VERSION 5.6 ;

BUSBITCHARS "[]" ;
DIVIDERCHAR "/" ;

UNITS
  DATABASE MICRONS 2000 ;
END UNITS

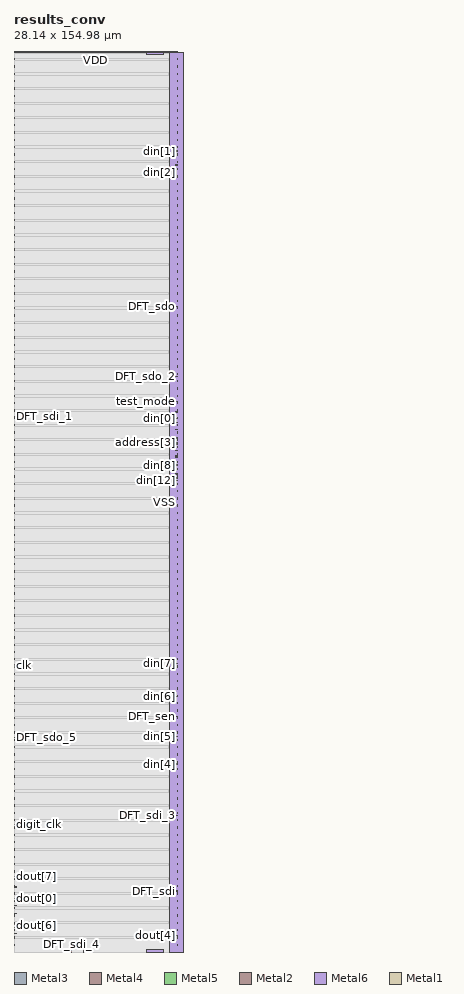
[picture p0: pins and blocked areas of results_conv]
MACRO results_conv
  CLASS BLOCK ;
  FOREIGN results_conv 0 0 ;
  ORIGIN 0.0000 0.0000 ;
  SIZE 28.1400 BY 154.9800 ;
  SYMMETRY X Y R90 ;
  PIN clk
    DIRECTION INPUT ;
    USE SIGNAL ;
    ANTENNAGATEAREA  0.039 ;
    PORT
      LAYER Metal3 ;
        RECT 0.0000 49.3850 0.4000 49.4550 ;
    END
  END clk
  PIN reset
    DIRECTION INPUT ;
    USE SIGNAL ;
    ANTENNAGATEAREA  0.039 ;
    PORT
      LAYER Metal4 ;
        RECT 11.9350 0.0000 12.0050 0.4000 ;
    END
  END reset
  PIN rcc_clk
    DIRECTION INPUT ;
    USE SIGNAL ;
    ANTENNAGATEAREA  0.039 ;
    PORT
      LAYER Metal3 ;
        RECT 27.7400 92.9250 28.1400 92.9950 ;
    END
  END rcc_clk
  PIN address[3]
    DIRECTION INPUT ;
    USE SIGNAL ;
    ANTENNAGATEAREA  0.039 ;
    PORT
      LAYER Metal5 ;
        RECT 27.7400 87.7450 28.1400 87.8150 ;
    END
  END address[3]
  PIN address[2]
    DIRECTION INPUT ;
    USE SIGNAL ;
    ANTENNAGATEAREA  0.039 ;
    PORT
      LAYER Metal3 ;
        RECT 27.7400 88.4450 28.1400 88.5150 ;
    END
  END address[2]
  PIN address[1]
    DIRECTION INPUT ;
    USE SIGNAL ;
    ANTENNAGATEAREA  0.039 ;
    PORT
      LAYER Metal5 ;
        RECT 27.7400 88.5850 28.1400 88.6550 ;
    END
  END address[1]
  PIN address[0]
    DIRECTION INPUT ;
    USE SIGNAL ;
    ANTENNAGATEAREA  0.039 ;
    PORT
      LAYER Metal5 ;
        RECT 27.7400 89.9850 28.1400 90.0550 ;
    END
  END address[0]
  PIN din[15]
    DIRECTION INPUT ;
    USE SIGNAL ;
    ANTENNAGATEAREA  0.039 ;
    PORT
      LAYER Metal5 ;
        RECT 27.7400 85.2250 28.1400 85.2950 ;
    END
  END din[15]
  PIN din[14]
    DIRECTION INPUT ;
    USE SIGNAL ;
    ANTENNAGATEAREA  0.039 ;
    PORT
      LAYER Metal5 ;
        RECT 27.7400 82.2850 28.1400 82.3550 ;
    END
  END din[14]
  PIN din[13]
    DIRECTION INPUT ;
    USE SIGNAL ;
    ANTENNAGATEAREA  0.039 ;
    PORT
      LAYER Metal3 ;
        RECT 27.7400 81.5850 28.1400 81.6550 ;
    END
  END din[13]
  PIN din[12]
    DIRECTION INPUT ;
    USE SIGNAL ;
    ANTENNAGATEAREA  0.039 ;
    PORT
      LAYER Metal5 ;
        RECT 27.7400 81.1650 28.1400 81.2350 ;
    END
  END din[12]
  PIN din[11]
    DIRECTION INPUT ;
    USE SIGNAL ;
    ANTENNAGATEAREA  0.039 ;
    PORT
      LAYER Metal5 ;
        RECT 27.7400 91.1050 28.1400 91.1750 ;
    END
  END din[11]
  PIN din[10]
    DIRECTION INPUT ;
    USE SIGNAL ;
    ANTENNAGATEAREA  0.039 ;
    PORT
      LAYER Metal3 ;
        RECT 27.7400 86.3450 28.1400 86.4150 ;
    END
  END din[10]
  PIN din[9]
    DIRECTION INPUT ;
    USE SIGNAL ;
    ANTENNAGATEAREA  0.039 ;
    PORT
      LAYER Metal3 ;
        RECT 27.7400 85.3650 28.1400 85.4350 ;
    END
  END din[9]
  PIN din[8]
    DIRECTION INPUT ;
    USE SIGNAL ;
    ANTENNAGATEAREA  0.039 ;
    PORT
      LAYER Metal3 ;
        RECT 27.7400 83.8250 28.1400 83.8950 ;
    END
  END din[8]
  PIN din[7]
    DIRECTION INPUT ;
    USE SIGNAL ;
    ANTENNAGATEAREA  0.039 ;
    PORT
      LAYER Metal5 ;
        RECT 27.7400 49.6650 28.1400 49.7350 ;
    END
  END din[7]
  PIN din[6]
    DIRECTION INPUT ;
    USE SIGNAL ;
    ANTENNAGATEAREA  0.039 ;
    PORT
      LAYER Metal5 ;
        RECT 27.7400 43.9250 28.1400 43.9950 ;
    END
  END din[6]
  PIN din[5]
    DIRECTION INPUT ;
    USE SIGNAL ;
    ANTENNAGATEAREA  0.039 ;
    PORT
      LAYER Metal5 ;
        RECT 27.7400 37.0650 28.1400 37.1350 ;
    END
  END din[5]
  PIN din[4]
    DIRECTION INPUT ;
    USE SIGNAL ;
    ANTENNAGATEAREA  0.039 ;
    PORT
      LAYER Metal5 ;
        RECT 27.7400 32.3050 28.1400 32.3750 ;
    END
  END din[4]
  PIN din[3]
    DIRECTION INPUT ;
    USE SIGNAL ;
    ANTENNAGATEAREA  0.039 ;
    PORT
      LAYER Metal5 ;
        RECT 27.7400 87.4650 28.1400 87.5350 ;
    END
  END din[3]
  PIN din[2]
    DIRECTION INPUT ;
    USE SIGNAL ;
    ANTENNAGATEAREA  0.039 ;
    PORT
      LAYER Metal5 ;
        RECT 27.7400 135.4850 28.1400 135.5550 ;
    END
  END din[2]
  PIN din[1]
    DIRECTION INPUT ;
    USE SIGNAL ;
    ANTENNAGATEAREA  0.039 ;
    PORT
      LAYER Metal3 ;
        RECT 27.7400 137.8650 28.1400 137.9350 ;
    END
  END din[1]
  PIN din[0]
    DIRECTION INPUT ;
    USE SIGNAL ;
    ANTENNAGATEAREA  0.039 ;
    PORT
      LAYER Metal3 ;
        RECT 27.7400 91.8050 28.1400 91.8750 ;
    END
  END din[0]
  PIN digit_clk
    DIRECTION OUTPUT ;
    USE SIGNAL ;
    ANTENNADIFFAREA 1.7285  LAYER Metal1 ;
    PORT
      LAYER Metal5 ;
        RECT 0.0000 21.9450 0.4000 22.0150 ;
    END
  END digit_clk
  PIN dout[7]
    DIRECTION OUTPUT ;
    USE SIGNAL ;
    ANTENNADIFFAREA 1.7285  LAYER Metal1 ;
    PORT
      LAYER Metal5 ;
        RECT 0.0000 12.9850 0.4000 13.0550 ;
    END
  END dout[7]
  PIN dout[6]
    DIRECTION OUTPUT ;
    USE SIGNAL ;
    ANTENNADIFFAREA 1.7285  LAYER Metal1 ;
    PORT
      LAYER Metal5 ;
        RECT 0.0000 3.1850 0.4000 3.2550 ;
    END
  END dout[6]
  PIN dout[5]
    DIRECTION OUTPUT ;
    USE SIGNAL ;
    ANTENNADIFFAREA 1.7285  LAYER Metal1 ;
    PORT
      LAYER Metal3 ;
        RECT 0.0000 4.1650 0.4000 4.2350 ;
    END
  END dout[5]
  PIN dout[4]
    DIRECTION OUTPUT ;
    USE SIGNAL ;
    ANTENNADIFFAREA 1.7285  LAYER Metal1 ;
    PORT
      LAYER Metal3 ;
        RECT 27.7400 2.7650 28.1400 2.8350 ;
    END
  END dout[4]
  PIN dout[3]
    DIRECTION OUTPUT ;
    USE SIGNAL ;
    ANTENNADIFFAREA 1.7285  LAYER Metal1 ;
    PORT
      LAYER Metal5 ;
        RECT 0.0000 4.7250 0.4000 4.7950 ;
    END
  END dout[3]
  PIN dout[2]
    DIRECTION OUTPUT ;
    USE SIGNAL ;
    ANTENNADIFFAREA 1.7285  LAYER Metal1 ;
    PORT
      LAYER Metal3 ;
        RECT 0.0000 6.5450 0.4000 6.6150 ;
    END
  END dout[2]
  PIN dout[1]
    DIRECTION OUTPUT ;
    USE SIGNAL ;
    ANTENNADIFFAREA 1.7285  LAYER Metal1 ;
    PORT
      LAYER Metal5 ;
        RECT 0.0000 7.9450 0.4000 8.0150 ;
    END
  END dout[1]
  PIN dout[0]
    DIRECTION OUTPUT ;
    USE SIGNAL ;
    ANTENNADIFFAREA 1.7285  LAYER Metal1 ;
    PORT
      LAYER Metal3 ;
        RECT 0.0000 9.2050 0.4000 9.2750 ;
    END
  END dout[0]
  PIN dout_flag
    DIRECTION OUTPUT ;
    USE SIGNAL ;
    ANTENNADIFFAREA 1.7285  LAYER Metal1 ;
    PORT
      LAYER Metal3 ;
        RECT 0.0000 11.1650 0.4000 11.2350 ;
    END
  END dout_flag
  PIN test_mode
    DIRECTION INPUT ;
    USE SIGNAL ;
    ANTENNAGATEAREA  0.039 ;
    PORT
      LAYER Metal5 ;
        RECT 27.7400 94.7450 28.1400 94.8150 ;
    END
  END test_mode
  PIN DFT_sdi
    DIRECTION INPUT ;
    USE SIGNAL ;
    ANTENNAGATEAREA  0.039 ;
    PORT
      LAYER Metal5 ;
        RECT 27.7400 10.4650 28.1400 10.5350 ;
    END
  END DFT_sdi
  PIN DFT_sen
    DIRECTION INPUT ;
    USE SIGNAL ;
    ANTENNAGATEAREA  0.039 ;
    PORT
      LAYER Metal3 ;
        RECT 27.7400 40.5650 28.1400 40.6350 ;
    END
  END DFT_sen
  PIN DFT_sdo
    DIRECTION OUTPUT ;
    USE SIGNAL ;
    ANTENNADIFFAREA 1.7285  LAYER Metal1 ;
    PORT
      LAYER Metal3 ;
        RECT 27.7400 111.1250 28.1400 111.1950 ;
    END
  END DFT_sdo
  PIN DFT_sdi_1
    DIRECTION INPUT ;
    USE SIGNAL ;
    ANTENNAGATEAREA  0.039 ;
    PORT
      LAYER Metal5 ;
        RECT 0.0000 92.2250 0.4000 92.2950 ;
    END
  END DFT_sdi_1
  PIN DFT_sdo_2
    DIRECTION OUTPUT ;
    USE SIGNAL ;
    ANTENNADIFFAREA 1.7285  LAYER Metal1 ;
    PORT
      LAYER Metal5 ;
        RECT 27.7400 99.0850 28.1400 99.1550 ;
    END
  END DFT_sdo_2
  PIN DFT_sdi_3
    DIRECTION INPUT ;
    USE SIGNAL ;
    ANTENNAGATEAREA  0.039 ;
    PORT
      LAYER Metal5 ;
        RECT 27.7400 23.4850 28.1400 23.5550 ;
    END
  END DFT_sdi_3
  PIN DFT_sdi_4
    DIRECTION INPUT ;
    USE SIGNAL ;
    ANTENNAGATEAREA  0.039 ;
    PORT
      LAYER Metal2 ;
        RECT 9.8350 0.0000 9.9050 0.4000 ;
    END
  END DFT_sdi_4
  PIN DFT_sdo_5
    DIRECTION OUTPUT ;
    USE SIGNAL ;
    ANTENNADIFFAREA 1.7285  LAYER Metal1 ;
    PORT
      LAYER Metal3 ;
        RECT 0.0000 36.9250 0.4000 36.9950 ;
    END
  END DFT_sdo_5
  PIN VSS
    DIRECTION INOUT ;
    USE GROUND ;
    PORT
      LAYER Metal6 ;
        RECT 26.7600 0.0000 29.7600 154.9800 ;
    END
    PORT
      LAYER Metal1 ;
        RECT 28.0700 15.0050 28.1400 15.2350 ;
    END
    PORT
      LAYER Metal1 ;
        RECT 0.0000 15.0050 0.0700 15.2350 ;
    END
    PORT
      LAYER Metal1 ;
        RECT 28.0700 12.4850 28.1400 12.7150 ;
    END
    PORT
      LAYER Metal1 ;
        RECT 0.0000 12.4850 0.0700 12.7150 ;
    END
    PORT
      LAYER Metal1 ;
        RECT 28.0700 9.9650 28.1400 10.1950 ;
    END
    PORT
      LAYER Metal1 ;
        RECT 0.0000 9.9650 0.0700 10.1950 ;
    END
    PORT
      LAYER Metal1 ;
        RECT 28.0700 7.4450 28.1400 7.6750 ;
    END
    PORT
      LAYER Metal1 ;
        RECT 0.0000 7.4450 0.0700 7.6750 ;
    END
    PORT
      LAYER Metal1 ;
        RECT 28.0700 2.4050 28.1400 2.6350 ;
    END
    PORT
      LAYER Metal1 ;
        RECT 0.0000 2.4050 0.0700 2.6350 ;
    END
    PORT
      LAYER Metal1 ;
        RECT 28.0700 4.9250 28.1400 5.1550 ;
    END
    PORT
      LAYER Metal1 ;
        RECT 0.0000 4.9250 0.0700 5.1550 ;
    END
    PORT
      LAYER Metal1 ;
        RECT 28.0700 37.6850 28.1400 37.9150 ;
    END
    PORT
      LAYER Metal1 ;
        RECT 0.0000 37.6850 0.0700 37.9150 ;
    END
    PORT
      LAYER Metal1 ;
        RECT 28.0700 35.1650 28.1400 35.3950 ;
    END
    PORT
      LAYER Metal1 ;
        RECT 0.0000 35.1650 0.0700 35.3950 ;
    END
    PORT
      LAYER Metal1 ;
        RECT 28.0700 32.6450 28.1400 32.8750 ;
    END
    PORT
      LAYER Metal1 ;
        RECT 0.0000 32.6450 0.0700 32.8750 ;
    END
    PORT
      LAYER Metal1 ;
        RECT 28.0700 30.1250 28.1400 30.3550 ;
    END
    PORT
      LAYER Metal1 ;
        RECT 0.0000 30.1250 0.0700 30.3550 ;
    END
    PORT
      LAYER Metal1 ;
        RECT 28.0700 27.6050 28.1400 27.8350 ;
    END
    PORT
      LAYER Metal1 ;
        RECT 0.0000 27.6050 0.0700 27.8350 ;
    END
    PORT
      LAYER Metal1 ;
        RECT 28.0700 25.0850 28.1400 25.3150 ;
    END
    PORT
      LAYER Metal1 ;
        RECT 0.0000 25.0850 0.0700 25.3150 ;
    END
    PORT
      LAYER Metal1 ;
        RECT 28.0700 22.5650 28.1400 22.7950 ;
    END
    PORT
      LAYER Metal1 ;
        RECT 0.0000 22.5650 0.0700 22.7950 ;
    END
    PORT
      LAYER Metal1 ;
        RECT 28.0700 20.0450 28.1400 20.2750 ;
    END
    PORT
      LAYER Metal1 ;
        RECT 0.0000 20.0450 0.0700 20.2750 ;
    END
    PORT
      LAYER Metal1 ;
        RECT 28.0700 17.5250 28.1400 17.7550 ;
    END
    PORT
      LAYER Metal1 ;
        RECT 0.0000 17.5250 0.0700 17.7550 ;
    END
    PORT
      LAYER Metal1 ;
        RECT 28.0700 57.8450 28.1400 58.0750 ;
    END
    PORT
      LAYER Metal1 ;
        RECT 0.0000 57.8450 0.0700 58.0750 ;
    END
    PORT
      LAYER Metal1 ;
        RECT 28.0700 60.3650 28.1400 60.5950 ;
    END
    PORT
      LAYER Metal1 ;
        RECT 0.0000 60.3650 0.0700 60.5950 ;
    END
    PORT
      LAYER Metal1 ;
        RECT 28.0700 55.3250 28.1400 55.5550 ;
    END
    PORT
      LAYER Metal1 ;
        RECT 0.0000 55.3250 0.0700 55.5550 ;
    END
    PORT
      LAYER Metal1 ;
        RECT 28.0700 52.8050 28.1400 53.0350 ;
    END
    PORT
      LAYER Metal1 ;
        RECT 0.0000 52.8050 0.0700 53.0350 ;
    END
    PORT
      LAYER Metal1 ;
        RECT 28.0700 50.2850 28.1400 50.5150 ;
    END
    PORT
      LAYER Metal1 ;
        RECT 0.0000 50.2850 0.0700 50.5150 ;
    END
    PORT
      LAYER Metal1 ;
        RECT 28.0700 47.7650 28.1400 47.9950 ;
    END
    PORT
      LAYER Metal1 ;
        RECT 0.0000 47.7650 0.0700 47.9950 ;
    END
    PORT
      LAYER Metal1 ;
        RECT 28.0700 45.2450 28.1400 45.4750 ;
    END
    PORT
      LAYER Metal1 ;
        RECT 0.0000 45.2450 0.0700 45.4750 ;
    END
    PORT
      LAYER Metal1 ;
        RECT 28.0700 42.7250 28.1400 42.9550 ;
    END
    PORT
      LAYER Metal1 ;
        RECT 0.0000 42.7250 0.0700 42.9550 ;
    END
    PORT
      LAYER Metal1 ;
        RECT 28.0700 40.2050 28.1400 40.4350 ;
    END
    PORT
      LAYER Metal1 ;
        RECT 0.0000 40.2050 0.0700 40.4350 ;
    END
    PORT
      LAYER Metal1 ;
        RECT 28.0700 78.0050 28.1400 78.2350 ;
    END
    PORT
      LAYER Metal1 ;
        RECT 0.0000 78.0050 0.0700 78.2350 ;
    END
    PORT
      LAYER Metal1 ;
        RECT 28.0700 75.4850 28.1400 75.7150 ;
    END
    PORT
      LAYER Metal1 ;
        RECT 0.0000 75.4850 0.0700 75.7150 ;
    END
    PORT
      LAYER Metal1 ;
        RECT 28.0700 72.9650 28.1400 73.1950 ;
    END
    PORT
      LAYER Metal1 ;
        RECT 0.0000 72.9650 0.0700 73.1950 ;
    END
    PORT
      LAYER Metal1 ;
        RECT 28.0700 80.5250 28.1400 80.7550 ;
    END
    PORT
      LAYER Metal1 ;
        RECT 0.0000 80.5250 0.0700 80.7550 ;
    END
    PORT
      LAYER Metal1 ;
        RECT 28.0700 83.0450 28.1400 83.2750 ;
    END
    PORT
      LAYER Metal1 ;
        RECT 0.0000 83.0450 0.0700 83.2750 ;
    END
    PORT
      LAYER Metal1 ;
        RECT 28.0700 70.4450 28.1400 70.6750 ;
    END
    PORT
      LAYER Metal1 ;
        RECT 0.0000 70.4450 0.0700 70.6750 ;
    END
    PORT
      LAYER Metal1 ;
        RECT 28.0700 67.9250 28.1400 68.1550 ;
    END
    PORT
      LAYER Metal1 ;
        RECT 0.0000 67.9250 0.0700 68.1550 ;
    END
    PORT
      LAYER Metal1 ;
        RECT 28.0700 65.4050 28.1400 65.6350 ;
    END
    PORT
      LAYER Metal1 ;
        RECT 0.0000 65.4050 0.0700 65.6350 ;
    END
    PORT
      LAYER Metal1 ;
        RECT 28.0700 62.8850 28.1400 63.1150 ;
    END
    PORT
      LAYER Metal1 ;
        RECT 0.0000 62.8850 0.0700 63.1150 ;
    END
    PORT
      LAYER Metal1 ;
        RECT 28.0700 105.7250 28.1400 105.9550 ;
    END
    PORT
      LAYER Metal1 ;
        RECT 0.0000 105.7250 0.0700 105.9550 ;
    END
    PORT
      LAYER Metal1 ;
        RECT 28.0700 103.2050 28.1400 103.4350 ;
    END
    PORT
      LAYER Metal1 ;
        RECT 0.0000 103.2050 0.0700 103.4350 ;
    END
    PORT
      LAYER Metal1 ;
        RECT 28.0700 100.6850 28.1400 100.9150 ;
    END
    PORT
      LAYER Metal1 ;
        RECT 0.0000 100.6850 0.0700 100.9150 ;
    END
    PORT
      LAYER Metal1 ;
        RECT 28.0700 98.1650 28.1400 98.3950 ;
    END
    PORT
      LAYER Metal1 ;
        RECT 0.0000 98.1650 0.0700 98.3950 ;
    END
    PORT
      LAYER Metal1 ;
        RECT 28.0700 95.6450 28.1400 95.8750 ;
    END
    PORT
      LAYER Metal1 ;
        RECT 0.0000 95.6450 0.0700 95.8750 ;
    END
    PORT
      LAYER Metal1 ;
        RECT 28.0700 93.1250 28.1400 93.3550 ;
    END
    PORT
      LAYER Metal1 ;
        RECT 0.0000 93.1250 0.0700 93.3550 ;
    END
    PORT
      LAYER Metal1 ;
        RECT 28.0700 90.6050 28.1400 90.8350 ;
    END
    PORT
      LAYER Metal1 ;
        RECT 0.0000 90.6050 0.0700 90.8350 ;
    END
    PORT
      LAYER Metal1 ;
        RECT 28.0700 88.0850 28.1400 88.3150 ;
    END
    PORT
      LAYER Metal1 ;
        RECT 0.0000 88.0850 0.0700 88.3150 ;
    END
    PORT
      LAYER Metal1 ;
        RECT 28.0700 85.5650 28.1400 85.7950 ;
    END
    PORT
      LAYER Metal1 ;
        RECT 0.0000 85.5650 0.0700 85.7950 ;
    END
    PORT
      LAYER Metal1 ;
        RECT 28.0700 128.4050 28.1400 128.6350 ;
    END
    PORT
      LAYER Metal1 ;
        RECT 0.0000 128.4050 0.0700 128.6350 ;
    END
    PORT
      LAYER Metal1 ;
        RECT 28.0700 125.8850 28.1400 126.1150 ;
    END
    PORT
      LAYER Metal1 ;
        RECT 0.0000 125.8850 0.0700 126.1150 ;
    END
    PORT
      LAYER Metal1 ;
        RECT 28.0700 123.3650 28.1400 123.5950 ;
    END
    PORT
      LAYER Metal1 ;
        RECT 0.0000 123.3650 0.0700 123.5950 ;
    END
    PORT
      LAYER Metal1 ;
        RECT 28.0700 120.8450 28.1400 121.0750 ;
    END
    PORT
      LAYER Metal1 ;
        RECT 0.0000 120.8450 0.0700 121.0750 ;
    END
    PORT
      LAYER Metal1 ;
        RECT 28.0700 118.3250 28.1400 118.5550 ;
    END
    PORT
      LAYER Metal1 ;
        RECT 0.0000 118.3250 0.0700 118.5550 ;
    END
    PORT
      LAYER Metal1 ;
        RECT 28.0700 115.8050 28.1400 116.0350 ;
    END
    PORT
      LAYER Metal1 ;
        RECT 0.0000 115.8050 0.0700 116.0350 ;
    END
    PORT
      LAYER Metal1 ;
        RECT 28.0700 113.2850 28.1400 113.5150 ;
    END
    PORT
      LAYER Metal1 ;
        RECT 0.0000 113.2850 0.0700 113.5150 ;
    END
    PORT
      LAYER Metal1 ;
        RECT 28.0700 110.7650 28.1400 110.9950 ;
    END
    PORT
      LAYER Metal1 ;
        RECT 0.0000 110.7650 0.0700 110.9950 ;
    END
    PORT
      LAYER Metal1 ;
        RECT 28.0700 108.2450 28.1400 108.4750 ;
    END
    PORT
      LAYER Metal1 ;
        RECT 0.0000 108.2450 0.0700 108.4750 ;
    END
    PORT
      LAYER Metal1 ;
        RECT 28.0700 151.0850 28.1400 151.3150 ;
    END
    PORT
      LAYER Metal1 ;
        RECT 0.0000 151.0850 0.0700 151.3150 ;
    END
    PORT
      LAYER Metal1 ;
        RECT 28.0700 141.0050 28.1400 141.2350 ;
    END
    PORT
      LAYER Metal1 ;
        RECT 0.0000 141.0050 0.0700 141.2350 ;
    END
    PORT
      LAYER Metal1 ;
        RECT 28.0700 143.5250 28.1400 143.7550 ;
    END
    PORT
      LAYER Metal1 ;
        RECT 0.0000 143.5250 0.0700 143.7550 ;
    END
    PORT
      LAYER Metal1 ;
        RECT 28.0700 146.0450 28.1400 146.2750 ;
    END
    PORT
      LAYER Metal1 ;
        RECT 0.0000 146.0450 0.0700 146.2750 ;
    END
    PORT
      LAYER Metal1 ;
        RECT 28.0700 148.5650 28.1400 148.7950 ;
    END
    PORT
      LAYER Metal1 ;
        RECT 0.0000 148.5650 0.0700 148.7950 ;
    END
    PORT
      LAYER Metal1 ;
        RECT 28.0700 138.4850 28.1400 138.7150 ;
    END
    PORT
      LAYER Metal1 ;
        RECT 0.0000 138.4850 0.0700 138.7150 ;
    END
    PORT
      LAYER Metal1 ;
        RECT 28.0700 133.4450 28.1400 133.6750 ;
    END
    PORT
      LAYER Metal1 ;
        RECT 0.0000 133.4450 0.0700 133.6750 ;
    END
    PORT
      LAYER Metal1 ;
        RECT 28.0700 135.9650 28.1400 136.1950 ;
    END
    PORT
      LAYER Metal1 ;
        RECT 0.0000 135.9650 0.0700 136.1950 ;
    END
    PORT
      LAYER Metal1 ;
        RECT 28.0700 130.9250 28.1400 131.1550 ;
    END
    PORT
      LAYER Metal1 ;
        RECT 0.0000 130.9250 0.0700 131.1550 ;
    END
    PORT
      LAYER Metal1 ;
        RECT 28.0700 153.6050 28.1400 153.8350 ;
    END
    PORT
      LAYER Metal1 ;
        RECT 0.0000 153.6050 0.0700 153.8350 ;
    END
  END VSS
  PIN VDD
    DIRECTION INOUT ;
    USE POWER ;
    PORT
      LAYER Metal1 ;
        RECT 0.0000 154.8650 28.1400 155.0950 ;
    END
    PORT
      LAYER Metal6 ;
        RECT 22.7600 0.0000 25.7600 0.4000 ;
    END
    PORT
      LAYER Metal6 ;
        RECT 22.7600 154.5800 25.7600 154.9800 ;
    END
    PORT
      LAYER Metal1 ;
        RECT 28.0700 13.7450 28.1400 13.9750 ;
    END
    PORT
      LAYER Metal1 ;
        RECT 0.0000 13.7450 0.0700 13.9750 ;
    END
    PORT
      LAYER Metal1 ;
        RECT 28.0700 11.2250 28.1400 11.4550 ;
    END
    PORT
      LAYER Metal1 ;
        RECT 0.0000 11.2250 0.0700 11.4550 ;
    END
    PORT
      LAYER Metal1 ;
        RECT 28.0700 8.7050 28.1400 8.9350 ;
    END
    PORT
      LAYER Metal1 ;
        RECT 0.0000 8.7050 0.0700 8.9350 ;
    END
    PORT
      LAYER Metal1 ;
        RECT 28.0700 6.1850 28.1400 6.4150 ;
    END
    PORT
      LAYER Metal1 ;
        RECT 0.0000 6.1850 0.0700 6.4150 ;
    END
    PORT
      LAYER Metal1 ;
        RECT 28.0700 3.6650 28.1400 3.8950 ;
    END
    PORT
      LAYER Metal1 ;
        RECT 0.0000 3.6650 0.0700 3.8950 ;
    END
    PORT
      LAYER Metal1 ;
        RECT 28.0700 1.1450 28.1400 1.3750 ;
    END
    PORT
      LAYER Metal1 ;
        RECT 0.0000 1.1450 0.0700 1.3750 ;
    END
    PORT
      LAYER Metal1 ;
        RECT 28.0700 16.2650 28.1400 16.4950 ;
    END
    PORT
      LAYER Metal1 ;
        RECT 0.0000 16.2650 0.0700 16.4950 ;
    END
    PORT
      LAYER Metal1 ;
        RECT 28.0700 36.4250 28.1400 36.6550 ;
    END
    PORT
      LAYER Metal1 ;
        RECT 0.0000 36.4250 0.0700 36.6550 ;
    END
    PORT
      LAYER Metal1 ;
        RECT 28.0700 33.9050 28.1400 34.1350 ;
    END
    PORT
      LAYER Metal1 ;
        RECT 0.0000 33.9050 0.0700 34.1350 ;
    END
    PORT
      LAYER Metal1 ;
        RECT 28.0700 31.3850 28.1400 31.6150 ;
    END
    PORT
      LAYER Metal1 ;
        RECT 0.0000 31.3850 0.0700 31.6150 ;
    END
    PORT
      LAYER Metal1 ;
        RECT 28.0700 28.8650 28.1400 29.0950 ;
    END
    PORT
      LAYER Metal1 ;
        RECT 0.0000 28.8650 0.0700 29.0950 ;
    END
    PORT
      LAYER Metal1 ;
        RECT 28.0700 23.8250 28.1400 24.0550 ;
    END
    PORT
      LAYER Metal1 ;
        RECT 0.0000 23.8250 0.0700 24.0550 ;
    END
    PORT
      LAYER Metal1 ;
        RECT 28.0700 26.3450 28.1400 26.5750 ;
    END
    PORT
      LAYER Metal1 ;
        RECT 0.0000 26.3450 0.0700 26.5750 ;
    END
    PORT
      LAYER Metal1 ;
        RECT 28.0700 21.3050 28.1400 21.5350 ;
    END
    PORT
      LAYER Metal1 ;
        RECT 0.0000 21.3050 0.0700 21.5350 ;
    END
    PORT
      LAYER Metal1 ;
        RECT 28.0700 18.7850 28.1400 19.0150 ;
    END
    PORT
      LAYER Metal1 ;
        RECT 0.0000 18.7850 0.0700 19.0150 ;
    END
    PORT
      LAYER Metal1 ;
        RECT 28.0700 56.5850 28.1400 56.8150 ;
    END
    PORT
      LAYER Metal1 ;
        RECT 0.0000 56.5850 0.0700 56.8150 ;
    END
    PORT
      LAYER Metal1 ;
        RECT 28.0700 59.1050 28.1400 59.3350 ;
    END
    PORT
      LAYER Metal1 ;
        RECT 0.0000 59.1050 0.0700 59.3350 ;
    END
    PORT
      LAYER Metal1 ;
        RECT 28.0700 54.0650 28.1400 54.2950 ;
    END
    PORT
      LAYER Metal1 ;
        RECT 0.0000 54.0650 0.0700 54.2950 ;
    END
    PORT
      LAYER Metal1 ;
        RECT 28.0700 51.5450 28.1400 51.7750 ;
    END
    PORT
      LAYER Metal1 ;
        RECT 0.0000 51.5450 0.0700 51.7750 ;
    END
    PORT
      LAYER Metal1 ;
        RECT 28.0700 49.0250 28.1400 49.2550 ;
    END
    PORT
      LAYER Metal1 ;
        RECT 0.0000 49.0250 0.0700 49.2550 ;
    END
    PORT
      LAYER Metal1 ;
        RECT 28.0700 46.5050 28.1400 46.7350 ;
    END
    PORT
      LAYER Metal1 ;
        RECT 0.0000 46.5050 0.0700 46.7350 ;
    END
    PORT
      LAYER Metal1 ;
        RECT 28.0700 43.9850 28.1400 44.2150 ;
    END
    PORT
      LAYER Metal1 ;
        RECT 0.0000 43.9850 0.0700 44.2150 ;
    END
    PORT
      LAYER Metal1 ;
        RECT 28.0700 41.4650 28.1400 41.6950 ;
    END
    PORT
      LAYER Metal1 ;
        RECT 0.0000 41.4650 0.0700 41.6950 ;
    END
    PORT
      LAYER Metal1 ;
        RECT 28.0700 38.9450 28.1400 39.1750 ;
    END
    PORT
      LAYER Metal1 ;
        RECT 0.0000 38.9450 0.0700 39.1750 ;
    END
    PORT
      LAYER Metal1 ;
        RECT 28.0700 76.7450 28.1400 76.9750 ;
    END
    PORT
      LAYER Metal1 ;
        RECT 0.0000 76.7450 0.0700 76.9750 ;
    END
    PORT
      LAYER Metal1 ;
        RECT 28.0700 71.7050 28.1400 71.9350 ;
    END
    PORT
      LAYER Metal1 ;
        RECT 0.0000 71.7050 0.0700 71.9350 ;
    END
    PORT
      LAYER Metal1 ;
        RECT 28.0700 74.2250 28.1400 74.4550 ;
    END
    PORT
      LAYER Metal1 ;
        RECT 0.0000 74.2250 0.0700 74.4550 ;
    END
    PORT
      LAYER Metal1 ;
        RECT 28.0700 79.2650 28.1400 79.4950 ;
    END
    PORT
      LAYER Metal1 ;
        RECT 0.0000 79.2650 0.0700 79.4950 ;
    END
    PORT
      LAYER Metal1 ;
        RECT 28.0700 81.7850 28.1400 82.0150 ;
    END
    PORT
      LAYER Metal1 ;
        RECT 0.0000 81.7850 0.0700 82.0150 ;
    END
    PORT
      LAYER Metal1 ;
        RECT 28.0700 66.6650 28.1400 66.8950 ;
    END
    PORT
      LAYER Metal1 ;
        RECT 0.0000 66.6650 0.0700 66.8950 ;
    END
    PORT
      LAYER Metal1 ;
        RECT 28.0700 69.1850 28.1400 69.4150 ;
    END
    PORT
      LAYER Metal1 ;
        RECT 0.0000 69.1850 0.0700 69.4150 ;
    END
    PORT
      LAYER Metal1 ;
        RECT 28.0700 64.1450 28.1400 64.3750 ;
    END
    PORT
      LAYER Metal1 ;
        RECT 0.0000 64.1450 0.0700 64.3750 ;
    END
    PORT
      LAYER Metal1 ;
        RECT 28.0700 61.6250 28.1400 61.8550 ;
    END
    PORT
      LAYER Metal1 ;
        RECT 0.0000 61.6250 0.0700 61.8550 ;
    END
    PORT
      LAYER Metal1 ;
        RECT 28.0700 104.4650 28.1400 104.6950 ;
    END
    PORT
      LAYER Metal1 ;
        RECT 0.0000 104.4650 0.0700 104.6950 ;
    END
    PORT
      LAYER Metal1 ;
        RECT 28.0700 101.9450 28.1400 102.1750 ;
    END
    PORT
      LAYER Metal1 ;
        RECT 0.0000 101.9450 0.0700 102.1750 ;
    END
    PORT
      LAYER Metal1 ;
        RECT 28.0700 96.9050 28.1400 97.1350 ;
    END
    PORT
      LAYER Metal1 ;
        RECT 0.0000 96.9050 0.0700 97.1350 ;
    END
    PORT
      LAYER Metal1 ;
        RECT 28.0700 99.4250 28.1400 99.6550 ;
    END
    PORT
      LAYER Metal1 ;
        RECT 0.0000 99.4250 0.0700 99.6550 ;
    END
    PORT
      LAYER Metal1 ;
        RECT 28.0700 94.3850 28.1400 94.6150 ;
    END
    PORT
      LAYER Metal1 ;
        RECT 0.0000 94.3850 0.0700 94.6150 ;
    END
    PORT
      LAYER Metal1 ;
        RECT 28.0700 91.8650 28.1400 92.0950 ;
    END
    PORT
      LAYER Metal1 ;
        RECT 0.0000 91.8650 0.0700 92.0950 ;
    END
    PORT
      LAYER Metal1 ;
        RECT 28.0700 89.3450 28.1400 89.5750 ;
    END
    PORT
      LAYER Metal1 ;
        RECT 0.0000 89.3450 0.0700 89.5750 ;
    END
    PORT
      LAYER Metal1 ;
        RECT 28.0700 86.8250 28.1400 87.0550 ;
    END
    PORT
      LAYER Metal1 ;
        RECT 0.0000 86.8250 0.0700 87.0550 ;
    END
    PORT
      LAYER Metal1 ;
        RECT 28.0700 84.3050 28.1400 84.5350 ;
    END
    PORT
      LAYER Metal1 ;
        RECT 0.0000 84.3050 0.0700 84.5350 ;
    END
    PORT
      LAYER Metal1 ;
        RECT 28.0700 127.1450 28.1400 127.3750 ;
    END
    PORT
      LAYER Metal1 ;
        RECT 0.0000 127.1450 0.0700 127.3750 ;
    END
    PORT
      LAYER Metal1 ;
        RECT 28.0700 124.6250 28.1400 124.8550 ;
    END
    PORT
      LAYER Metal1 ;
        RECT 0.0000 124.6250 0.0700 124.8550 ;
    END
    PORT
      LAYER Metal1 ;
        RECT 28.0700 122.1050 28.1400 122.3350 ;
    END
    PORT
      LAYER Metal1 ;
        RECT 0.0000 122.1050 0.0700 122.3350 ;
    END
    PORT
      LAYER Metal1 ;
        RECT 28.0700 119.5850 28.1400 119.8150 ;
    END
    PORT
      LAYER Metal1 ;
        RECT 0.0000 119.5850 0.0700 119.8150 ;
    END
    PORT
      LAYER Metal1 ;
        RECT 28.0700 117.0650 28.1400 117.2950 ;
    END
    PORT
      LAYER Metal1 ;
        RECT 0.0000 117.0650 0.0700 117.2950 ;
    END
    PORT
      LAYER Metal1 ;
        RECT 28.0700 114.5450 28.1400 114.7750 ;
    END
    PORT
      LAYER Metal1 ;
        RECT 0.0000 114.5450 0.0700 114.7750 ;
    END
    PORT
      LAYER Metal1 ;
        RECT 28.0700 112.0250 28.1400 112.2550 ;
    END
    PORT
      LAYER Metal1 ;
        RECT 0.0000 112.0250 0.0700 112.2550 ;
    END
    PORT
      LAYER Metal1 ;
        RECT 28.0700 109.5050 28.1400 109.7350 ;
    END
    PORT
      LAYER Metal1 ;
        RECT 0.0000 109.5050 0.0700 109.7350 ;
    END
    PORT
      LAYER Metal1 ;
        RECT 28.0700 106.9850 28.1400 107.2150 ;
    END
    PORT
      LAYER Metal1 ;
        RECT 0.0000 106.9850 0.0700 107.2150 ;
    END
    PORT
      LAYER Metal1 ;
        RECT 28.0700 149.8250 28.1400 150.0550 ;
    END
    PORT
      LAYER Metal1 ;
        RECT 0.0000 149.8250 0.0700 150.0550 ;
    END
    PORT
      LAYER Metal1 ;
        RECT 28.0700 142.2650 28.1400 142.4950 ;
    END
    PORT
      LAYER Metal1 ;
        RECT 0.0000 142.2650 0.0700 142.4950 ;
    END
    PORT
      LAYER Metal1 ;
        RECT 28.0700 144.7850 28.1400 145.0150 ;
    END
    PORT
      LAYER Metal1 ;
        RECT 0.0000 144.7850 0.0700 145.0150 ;
    END
    PORT
      LAYER Metal1 ;
        RECT 28.0700 147.3050 28.1400 147.5350 ;
    END
    PORT
      LAYER Metal1 ;
        RECT 0.0000 147.3050 0.0700 147.5350 ;
    END
    PORT
      LAYER Metal1 ;
        RECT 28.0700 139.7450 28.1400 139.9750 ;
    END
    PORT
      LAYER Metal1 ;
        RECT 0.0000 139.7450 0.0700 139.9750 ;
    END
    PORT
      LAYER Metal1 ;
        RECT 28.0700 134.7050 28.1400 134.9350 ;
    END
    PORT
      LAYER Metal1 ;
        RECT 0.0000 134.7050 0.0700 134.9350 ;
    END
    PORT
      LAYER Metal1 ;
        RECT 28.0700 137.2250 28.1400 137.4550 ;
    END
    PORT
      LAYER Metal1 ;
        RECT 0.0000 137.2250 0.0700 137.4550 ;
    END
    PORT
      LAYER Metal1 ;
        RECT 28.0700 132.1850 28.1400 132.4150 ;
    END
    PORT
      LAYER Metal1 ;
        RECT 0.0000 132.1850 0.0700 132.4150 ;
    END
    PORT
      LAYER Metal1 ;
        RECT 28.0700 129.6650 28.1400 129.8950 ;
    END
    PORT
      LAYER Metal1 ;
        RECT 0.0000 129.6650 0.0700 129.8950 ;
    END
    PORT
      LAYER Metal1 ;
        RECT 28.0700 152.3450 28.1400 152.5750 ;
    END
    PORT
      LAYER Metal1 ;
        RECT 0.0000 152.3450 0.0700 152.5750 ;
    END
  END VDD
  OBS
#    LAYER Metal6 ;
#      RECT 0.0000 0.0000 26.2600 154.3200 ;
#      RECT 0.0000 154.3200 22.3600 154.9800 ;
#      RECT 26.1600 154.3200 26.2600 154.9800 ;
#    LAYER Metal5 ;
#      RECT 0.0000 0.0000 28.1400 2.1100 ;
#      RECT 0.0000 2.1100 26.6100 2.9300 ;
#      RECT 0.0000 2.9300 28.1400 4.6300 ;
#      RECT 0.0000 4.6300 26.6100 5.4500 ;
#      RECT 0.0000 5.4500 28.1400 7.1500 ;
#      RECT 0.0000 7.1500 26.6100 7.9700 ;
#      RECT 0.0000 7.9700 28.1400 9.6700 ;
#      RECT 0.0000 9.6700 26.6100 10.4900 ;
#      RECT 0.0000 10.4900 28.1400 12.1900 ;
#      RECT 0.0000 12.1900 26.6100 13.0100 ;
#      RECT 0.0000 13.0100 28.1400 14.7100 ;
#      RECT 0.0000 14.7100 26.6100 15.5300 ;
#      RECT 0.0000 15.5300 28.1400 17.2300 ;
#      RECT 0.0000 17.2300 26.6100 18.0500 ;
#      RECT 0.0000 18.0500 28.1400 19.7500 ;
#      RECT 0.0000 19.7500 26.6100 20.5700 ;
#      RECT 0.0000 20.5700 28.1400 22.2700 ;
#      RECT 0.0000 22.2700 26.6100 23.0900 ;
#      RECT 0.0000 23.0900 28.1400 24.7900 ;
#      RECT 0.0000 24.7900 26.6100 25.6100 ;
#      RECT 0.0000 25.6100 28.1400 27.3100 ;
#      RECT 0.0000 27.3100 26.6100 28.1300 ;
#      RECT 0.0000 28.1300 28.1400 29.8300 ;
#      RECT 0.0000 29.8300 26.6100 30.6500 ;
#      RECT 0.0000 30.6500 28.1400 32.3500 ;
#      RECT 0.0000 32.3500 26.6100 33.1700 ;
#      RECT 0.0000 33.1700 28.1400 34.8700 ;
#      RECT 0.0000 34.8700 26.6100 35.6900 ;
#      RECT 0.0000 35.6900 28.1400 37.3900 ;
#      RECT 0.0000 37.3900 26.6100 38.2100 ;
#      RECT 0.0000 38.2100 28.1400 39.9100 ;
#      RECT 0.0000 39.9100 26.6100 40.7300 ;
#      RECT 0.0000 40.7300 28.1400 42.4300 ;
#      RECT 0.0000 42.4300 26.6100 43.2500 ;
#      RECT 0.0000 43.2500 28.1400 44.9500 ;
#      RECT 0.0000 44.9500 26.6100 45.7700 ;
#      RECT 0.0000 45.7700 28.1400 47.4700 ;
#      RECT 0.0000 47.4700 26.6100 48.2900 ;
#      RECT 0.0000 48.2900 28.1400 49.9900 ;
#      RECT 0.0000 49.9900 26.6100 50.8100 ;
#      RECT 0.0000 50.8100 28.1400 52.5100 ;
#      RECT 0.0000 52.5100 26.6100 53.3300 ;
#      RECT 0.0000 53.3300 28.1400 55.0300 ;
#      RECT 0.0000 55.0300 26.6100 55.8500 ;
#      RECT 0.0000 55.8500 28.1400 57.5500 ;
#      RECT 0.0000 57.5500 26.6100 58.3700 ;
#      RECT 0.0000 58.3700 28.1400 60.0700 ;
#      RECT 0.0000 60.0700 26.6100 60.8900 ;
#      RECT 0.0000 60.8900 28.1400 62.5900 ;
#      RECT 0.0000 62.5900 26.6100 63.4100 ;
#      RECT 0.0000 63.4100 28.1400 65.1100 ;
#      RECT 0.0000 65.1100 26.6100 65.9300 ;
#      RECT 0.0000 65.9300 28.1400 67.6300 ;
#      RECT 0.0000 67.6300 26.6100 68.4500 ;
#      RECT 0.0000 68.4500 28.1400 70.1500 ;
#      RECT 0.0000 70.1500 26.6100 70.9700 ;
#      RECT 0.0000 70.9700 28.1400 72.6700 ;
#      RECT 0.0000 72.6700 26.6100 73.4900 ;
#      RECT 0.0000 73.4900 28.1400 75.1900 ;
#      RECT 0.0000 75.1900 26.6100 76.0100 ;
#      RECT 0.0000 76.0100 28.1400 77.7100 ;
#      RECT 0.0000 77.7100 26.6100 78.5300 ;
#      RECT 0.0000 78.5300 28.1400 80.2300 ;
#      RECT 0.0000 80.2300 26.6100 81.0500 ;
#      RECT 0.0000 81.0500 28.1400 82.7500 ;
#      RECT 0.0000 82.7500 26.6100 83.5700 ;
#      RECT 0.0000 83.5700 28.1400 85.2700 ;
#      RECT 0.0000 85.2700 26.6100 86.0900 ;
#      RECT 0.0000 86.0900 28.1400 87.7900 ;
#      RECT 0.0000 87.7900 26.6100 88.6100 ;
#      RECT 0.0000 88.6100 28.1400 90.3100 ;
#      RECT 0.0000 90.3100 26.6100 91.1300 ;
#      RECT 0.0000 91.1300 28.1400 92.8300 ;
#      RECT 0.0000 92.8300 26.6100 93.6500 ;
#      RECT 0.0000 93.6500 28.1400 95.3500 ;
#      RECT 0.0000 95.3500 26.6100 96.1700 ;
#      RECT 0.0000 96.1700 28.1400 97.8700 ;
#      RECT 0.0000 97.8700 26.6100 98.6900 ;
#      RECT 0.0000 98.6900 28.1400 100.3900 ;
#      RECT 0.0000 100.3900 26.6100 101.2100 ;
#      RECT 0.0000 101.2100 28.1400 102.9100 ;
#      RECT 0.0000 102.9100 26.6100 103.7300 ;
#      RECT 0.0000 103.7300 28.1400 105.4300 ;
#      RECT 0.0000 105.4300 26.6100 106.2500 ;
#      RECT 0.0000 106.2500 28.1400 107.9500 ;
#      RECT 0.0000 107.9500 26.6100 108.7700 ;
#      RECT 0.0000 108.7700 28.1400 110.4700 ;
#      RECT 0.0000 110.4700 26.6100 111.2900 ;
#      RECT 0.0000 111.2900 28.1400 112.9900 ;
#      RECT 0.0000 112.9900 26.6100 113.8100 ;
#      RECT 0.0000 113.8100 28.1400 115.5100 ;
#      RECT 0.0000 115.5100 26.6100 116.3300 ;
#      RECT 0.0000 116.3300 28.1400 118.0300 ;
#      RECT 0.0000 118.0300 26.6100 118.8500 ;
#      RECT 0.0000 118.8500 28.1400 120.5500 ;
#      RECT 0.0000 120.5500 26.6100 121.3700 ;
#      RECT 0.0000 121.3700 28.1400 123.0700 ;
#      RECT 0.0000 123.0700 26.6100 123.8900 ;
#      RECT 0.0000 123.8900 28.1400 125.5900 ;
#      RECT 0.0000 125.5900 26.6100 126.4100 ;
#      RECT 0.0000 126.4100 28.1400 128.1100 ;
#      RECT 0.0000 128.1100 26.6100 128.9300 ;
#      RECT 0.0000 128.9300 28.1400 130.6300 ;
#      RECT 0.0000 130.6300 26.6100 131.4500 ;
#      RECT 0.0000 131.4500 28.1400 133.1500 ;
#      RECT 0.0000 133.1500 26.6100 133.9700 ;
#      RECT 0.0000 133.9700 28.1400 135.6700 ;
#      RECT 0.0000 135.6700 26.6100 136.4900 ;
#      RECT 0.0000 136.4900 28.1400 138.1900 ;
#      RECT 0.0000 138.1900 26.6100 139.0100 ;
#      RECT 0.0000 139.0100 28.1400 140.7100 ;
#      RECT 0.0000 140.7100 26.6100 141.5300 ;
#      RECT 0.0000 141.5300 28.1400 143.2300 ;
#      RECT 0.0000 143.2300 26.6100 144.0500 ;
#      RECT 0.0000 144.0500 28.1400 145.7500 ;
#      RECT 0.0000 145.7500 26.6100 146.5700 ;
#      RECT 0.0000 146.5700 28.1400 148.2700 ;
#      RECT 0.0000 148.2700 26.6100 149.0900 ;
#      RECT 0.0000 149.0900 28.1400 150.7900 ;
#      RECT 0.0000 150.7900 26.6100 151.6100 ;
#      RECT 0.0000 151.6100 28.1400 153.3100 ;
#      RECT 0.0000 153.3100 26.6100 154.1300 ;
#      RECT 0.0000 154.1300 28.1400 154.5700 ;
#      RECT 0.0000 154.5700 22.6100 154.9800 ;
#      RECT 25.9100 154.5700 28.1400 154.9800 ;
    LAYER Metal4 ;
      RECT 0.0000 0.0000 28.1400 2.3050 ;
      RECT 0.0000 2.3050 26.6600 2.7350 ;
      RECT 0.0000 2.7350 28.1400 4.8250 ;
      RECT 0.0000 4.8250 26.6600 5.2550 ;
      RECT 0.0000 5.2550 28.1400 7.3450 ;
      RECT 0.0000 7.3450 26.6600 7.7750 ;
      RECT 0.0000 7.7750 28.1400 9.8650 ;
      RECT 0.0000 9.8650 26.6600 10.2950 ;
      RECT 0.0000 10.2950 28.1400 12.3850 ;
      RECT 0.0000 12.3850 26.6600 12.8150 ;
      RECT 0.0000 12.8150 28.1400 14.9050 ;
      RECT 0.0000 14.9050 26.6600 15.3350 ;
      RECT 0.0000 15.3350 28.1400 17.4250 ;
      RECT 0.0000 17.4250 26.6600 17.8550 ;
      RECT 0.0000 17.8550 28.1400 19.9450 ;
      RECT 0.0000 19.9450 26.6600 20.3750 ;
      RECT 0.0000 20.3750 28.1400 22.4650 ;
      RECT 0.0000 22.4650 26.6600 22.8950 ;
      RECT 0.0000 22.8950 28.1400 24.9850 ;
      RECT 0.0000 24.9850 26.6600 25.4150 ;
      RECT 0.0000 25.4150 28.1400 27.5050 ;
      RECT 0.0000 27.5050 26.6600 27.9350 ;
      RECT 0.0000 27.9350 28.1400 30.0250 ;
      RECT 0.0000 30.0250 26.6600 30.4550 ;
      RECT 0.0000 30.4550 28.1400 32.5450 ;
      RECT 0.0000 32.5450 26.6600 32.9750 ;
      RECT 0.0000 32.9750 28.1400 35.0650 ;
      RECT 0.0000 35.0650 26.6600 35.4950 ;
      RECT 0.0000 35.4950 28.1400 37.5850 ;
      RECT 0.0000 37.5850 26.6600 38.0150 ;
      RECT 0.0000 38.0150 28.1400 40.1050 ;
      RECT 0.0000 40.1050 26.6600 40.5350 ;
      RECT 0.0000 40.5350 28.1400 42.6250 ;
      RECT 0.0000 42.6250 26.6600 43.0550 ;
      RECT 0.0000 43.0550 28.1400 45.1450 ;
      RECT 0.0000 45.1450 26.6600 45.5750 ;
      RECT 0.0000 45.5750 28.1400 47.6650 ;
      RECT 0.0000 47.6650 26.6600 48.0950 ;
      RECT 0.0000 48.0950 28.1400 50.1850 ;
      RECT 0.0000 50.1850 26.6600 50.6150 ;
      RECT 0.0000 50.6150 28.1400 52.7050 ;
      RECT 0.0000 52.7050 26.6600 53.1350 ;
      RECT 0.0000 53.1350 28.1400 55.2250 ;
      RECT 0.0000 55.2250 26.6600 55.6550 ;
      RECT 0.0000 55.6550 28.1400 57.7450 ;
      RECT 0.0000 57.7450 26.6600 58.1750 ;
      RECT 0.0000 58.1750 28.1400 60.2650 ;
      RECT 0.0000 60.2650 26.6600 60.6950 ;
      RECT 0.0000 60.6950 28.1400 62.7850 ;
      RECT 0.0000 62.7850 26.6600 63.2150 ;
      RECT 0.0000 63.2150 28.1400 65.3050 ;
      RECT 0.0000 65.3050 26.6600 65.7350 ;
      RECT 0.0000 65.7350 28.1400 67.8250 ;
      RECT 0.0000 67.8250 26.6600 68.2550 ;
      RECT 0.0000 68.2550 28.1400 70.3450 ;
      RECT 0.0000 70.3450 26.6600 70.7750 ;
      RECT 0.0000 70.7750 28.1400 72.8650 ;
      RECT 0.0000 72.8650 26.6600 73.2950 ;
      RECT 0.0000 73.2950 28.1400 75.3850 ;
      RECT 0.0000 75.3850 26.6600 75.8150 ;
      RECT 0.0000 75.8150 28.1400 77.9050 ;
      RECT 0.0000 77.9050 26.6600 78.3350 ;
      RECT 0.0000 78.3350 28.1400 80.4250 ;
      RECT 0.0000 80.4250 26.6600 80.8550 ;
      RECT 0.0000 80.8550 28.1400 82.9450 ;
      RECT 0.0000 82.9450 26.6600 83.3750 ;
      RECT 0.0000 83.3750 28.1400 85.4650 ;
      RECT 0.0000 85.4650 26.6600 85.8950 ;
      RECT 0.0000 85.8950 28.1400 87.9850 ;
      RECT 0.0000 87.9850 26.6600 88.4150 ;
      RECT 0.0000 88.4150 28.1400 90.5050 ;
      RECT 0.0000 90.5050 26.6600 90.9350 ;
      RECT 0.0000 90.9350 28.1400 93.0250 ;
      RECT 0.0000 93.0250 26.6600 93.4550 ;
      RECT 0.0000 93.4550 28.1400 95.5450 ;
      RECT 0.0000 95.5450 26.6600 95.9750 ;
      RECT 0.0000 95.9750 28.1400 98.0650 ;
      RECT 0.0000 98.0650 26.6600 98.4950 ;
      RECT 0.0000 98.4950 28.1400 100.5850 ;
      RECT 0.0000 100.5850 26.6600 101.0150 ;
      RECT 0.0000 101.0150 28.1400 103.1050 ;
      RECT 0.0000 103.1050 26.6600 103.5350 ;
      RECT 0.0000 103.5350 28.1400 105.6250 ;
      RECT 0.0000 105.6250 26.6600 106.0550 ;
      RECT 0.0000 106.0550 28.1400 108.1450 ;
      RECT 0.0000 108.1450 26.6600 108.5750 ;
      RECT 0.0000 108.5750 28.1400 110.6650 ;
      RECT 0.0000 110.6650 26.6600 111.0950 ;
      RECT 0.0000 111.0950 28.1400 113.1850 ;
      RECT 0.0000 113.1850 26.6600 113.6150 ;
      RECT 0.0000 113.6150 28.1400 115.7050 ;
      RECT 0.0000 115.7050 26.6600 116.1350 ;
      RECT 0.0000 116.1350 28.1400 118.2250 ;
      RECT 0.0000 118.2250 26.6600 118.6550 ;
      RECT 0.0000 118.6550 28.1400 120.7450 ;
      RECT 0.0000 120.7450 26.6600 121.1750 ;
      RECT 0.0000 121.1750 28.1400 123.2650 ;
      RECT 0.0000 123.2650 26.6600 123.6950 ;
      RECT 0.0000 123.6950 28.1400 125.7850 ;
      RECT 0.0000 125.7850 26.6600 126.2150 ;
      RECT 0.0000 126.2150 28.1400 128.3050 ;
      RECT 0.0000 128.3050 26.6600 128.7350 ;
      RECT 0.0000 128.7350 28.1400 130.8250 ;
      RECT 0.0000 130.8250 26.6600 131.2550 ;
      RECT 0.0000 131.2550 28.1400 133.3450 ;
      RECT 0.0000 133.3450 26.6600 133.7750 ;
      RECT 0.0000 133.7750 28.1400 135.8650 ;
      RECT 0.0000 135.8650 26.6600 136.2950 ;
      RECT 0.0000 136.2950 28.1400 138.3850 ;
      RECT 0.0000 138.3850 26.6600 138.8150 ;
      RECT 0.0000 138.8150 28.1400 140.9050 ;
      RECT 0.0000 140.9050 26.6600 141.3350 ;
      RECT 0.0000 141.3350 28.1400 143.4250 ;
      RECT 0.0000 143.4250 26.6600 143.8550 ;
      RECT 0.0000 143.8550 28.1400 145.9450 ;
      RECT 0.0000 145.9450 26.6600 146.3750 ;
      RECT 0.0000 146.3750 28.1400 148.4650 ;
      RECT 0.0000 148.4650 26.6600 148.8950 ;
      RECT 0.0000 148.8950 28.1400 150.9850 ;
      RECT 0.0000 150.9850 26.6600 151.4150 ;
      RECT 0.0000 151.4150 28.1400 153.5050 ;
      RECT 0.0000 153.5050 26.6600 153.9350 ;
      RECT 0.0000 153.9350 28.1400 154.7650 ;
      RECT 25.8600 154.7650 28.1400 154.9800 ;
      RECT 0.0000 154.7650 22.6600 154.9800 ;
    LAYER Metal3 ;
      RECT 0.0000 0.0000 28.1400 2.3050 ;
      RECT 0.0000 2.3050 26.6600 2.7350 ;
      RECT 0.0000 2.7350 28.1400 4.8250 ;
      RECT 0.0000 4.8250 26.6600 5.2550 ;
      RECT 0.0000 5.2550 28.1400 7.3450 ;
      RECT 0.0000 7.3450 26.6600 7.7750 ;
      RECT 0.0000 7.7750 28.1400 9.8650 ;
      RECT 0.0000 9.8650 26.6600 10.2950 ;
      RECT 0.0000 10.2950 28.1400 12.3850 ;
      RECT 0.0000 12.3850 26.6600 12.8150 ;
      RECT 0.0000 12.8150 28.1400 14.9050 ;
      RECT 0.0000 14.9050 26.6600 15.3350 ;
      RECT 0.0000 15.3350 28.1400 17.4250 ;
      RECT 0.0000 17.4250 26.6600 17.8550 ;
      RECT 0.0000 17.8550 28.1400 19.9450 ;
      RECT 0.0000 19.9450 26.6600 20.3750 ;
      RECT 0.0000 20.3750 28.1400 22.4650 ;
      RECT 0.0000 22.4650 26.6600 22.8950 ;
      RECT 0.0000 22.8950 28.1400 24.9850 ;
      RECT 0.0000 24.9850 26.6600 25.4150 ;
      RECT 0.0000 25.4150 28.1400 27.5050 ;
      RECT 0.0000 27.5050 26.6600 27.9350 ;
      RECT 0.0000 27.9350 28.1400 30.0250 ;
      RECT 0.0000 30.0250 26.6600 30.4550 ;
      RECT 0.0000 30.4550 28.1400 32.5450 ;
      RECT 0.0000 32.5450 26.6600 32.9750 ;
      RECT 0.0000 32.9750 28.1400 35.0650 ;
      RECT 0.0000 35.0650 26.6600 35.4950 ;
      RECT 0.0000 35.4950 28.1400 37.5850 ;
      RECT 0.0000 37.5850 26.6600 38.0150 ;
      RECT 0.0000 38.0150 28.1400 40.1050 ;
      RECT 0.0000 40.1050 26.6600 40.5350 ;
      RECT 0.0000 40.5350 28.1400 42.6250 ;
      RECT 0.0000 42.6250 26.6600 43.0550 ;
      RECT 0.0000 43.0550 28.1400 45.1450 ;
      RECT 0.0000 45.1450 26.6600 45.5750 ;
      RECT 0.0000 45.5750 28.1400 47.6650 ;
      RECT 0.0000 47.6650 26.6600 48.0950 ;
      RECT 0.0000 48.0950 28.1400 50.1850 ;
      RECT 0.0000 50.1850 26.6600 50.6150 ;
      RECT 0.0000 50.6150 28.1400 52.7050 ;
      RECT 0.0000 52.7050 26.6600 53.1350 ;
      RECT 0.0000 53.1350 28.1400 55.2250 ;
      RECT 0.0000 55.2250 26.6600 55.6550 ;
      RECT 0.0000 55.6550 28.1400 57.7450 ;
      RECT 0.0000 57.7450 26.6600 58.1750 ;
      RECT 0.0000 58.1750 28.1400 60.2650 ;
      RECT 0.0000 60.2650 26.6600 60.6950 ;
      RECT 0.0000 60.6950 28.1400 62.7850 ;
      RECT 0.0000 62.7850 26.6600 63.2150 ;
      RECT 0.0000 63.2150 28.1400 65.3050 ;
      RECT 0.0000 65.3050 26.6600 65.7350 ;
      RECT 0.0000 65.7350 28.1400 67.8250 ;
      RECT 0.0000 67.8250 26.6600 68.2550 ;
      RECT 0.0000 68.2550 28.1400 70.3450 ;
      RECT 0.0000 70.3450 26.6600 70.7750 ;
      RECT 0.0000 70.7750 28.1400 72.8650 ;
      RECT 0.0000 72.8650 26.6600 73.2950 ;
      RECT 0.0000 73.2950 28.1400 75.3850 ;
      RECT 0.0000 75.3850 26.6600 75.8150 ;
      RECT 0.0000 75.8150 28.1400 77.9050 ;
      RECT 0.0000 77.9050 26.6600 78.3350 ;
      RECT 0.0000 78.3350 28.1400 80.4250 ;
      RECT 0.0000 80.4250 26.6600 80.8550 ;
      RECT 0.0000 80.8550 28.1400 82.9450 ;
      RECT 0.0000 82.9450 26.6600 83.3750 ;
      RECT 0.0000 83.3750 28.1400 85.4650 ;
      RECT 0.0000 85.4650 26.6600 85.8950 ;
      RECT 0.0000 85.8950 28.1400 87.9850 ;
      RECT 0.0000 87.9850 26.6600 88.4150 ;
      RECT 0.0000 88.4150 28.1400 90.5050 ;
      RECT 0.0000 90.5050 26.6600 90.9350 ;
      RECT 0.0000 90.9350 28.1400 93.0250 ;
      RECT 0.0000 93.0250 26.6600 93.4550 ;
      RECT 0.0000 93.4550 28.1400 95.5450 ;
      RECT 0.0000 95.5450 26.6600 95.9750 ;
      RECT 0.0000 95.9750 28.1400 98.0650 ;
      RECT 0.0000 98.0650 26.6600 98.4950 ;
      RECT 0.0000 98.4950 28.1400 100.5850 ;
      RECT 0.0000 100.5850 26.6600 101.0150 ;
      RECT 0.0000 101.0150 28.1400 103.1050 ;
      RECT 0.0000 103.1050 26.6600 103.5350 ;
      RECT 0.0000 103.5350 28.1400 105.6250 ;
      RECT 0.0000 105.6250 26.6600 106.0550 ;
      RECT 0.0000 106.0550 28.1400 108.1450 ;
      RECT 0.0000 108.1450 26.6600 108.5750 ;
      RECT 0.0000 108.5750 28.1400 110.6650 ;
      RECT 0.0000 110.6650 26.6600 111.0950 ;
      RECT 0.0000 111.0950 28.1400 113.1850 ;
      RECT 0.0000 113.1850 26.6600 113.6150 ;
      RECT 0.0000 113.6150 28.1400 115.7050 ;
      RECT 0.0000 115.7050 26.6600 116.1350 ;
      RECT 0.0000 116.1350 28.1400 118.2250 ;
      RECT 0.0000 118.2250 26.6600 118.6550 ;
      RECT 0.0000 118.6550 28.1400 120.7450 ;
      RECT 0.0000 120.7450 26.6600 121.1750 ;
      RECT 0.0000 121.1750 28.1400 123.2650 ;
      RECT 0.0000 123.2650 26.6600 123.6950 ;
      RECT 0.0000 123.6950 28.1400 125.7850 ;
      RECT 0.0000 125.7850 26.6600 126.2150 ;
      RECT 0.0000 126.2150 28.1400 128.3050 ;
      RECT 0.0000 128.3050 26.6600 128.7350 ;
      RECT 0.0000 128.7350 28.1400 130.8250 ;
      RECT 0.0000 130.8250 26.6600 131.2550 ;
      RECT 0.0000 131.2550 28.1400 133.3450 ;
      RECT 0.0000 133.3450 26.6600 133.7750 ;
      RECT 0.0000 133.7750 28.1400 135.8650 ;
      RECT 0.0000 135.8650 26.6600 136.2950 ;
      RECT 0.0000 136.2950 28.1400 138.3850 ;
      RECT 0.0000 138.3850 26.6600 138.8150 ;
      RECT 0.0000 138.8150 28.1400 140.9050 ;
      RECT 0.0000 140.9050 26.6600 141.3350 ;
      RECT 0.0000 141.3350 28.1400 143.4250 ;
      RECT 0.0000 143.4250 26.6600 143.8550 ;
      RECT 0.0000 143.8550 28.1400 145.9450 ;
      RECT 0.0000 145.9450 26.6600 146.3750 ;
      RECT 0.0000 146.3750 28.1400 148.4650 ;
      RECT 0.0000 148.4650 26.6600 148.8950 ;
      RECT 0.0000 148.8950 28.1400 150.9850 ;
      RECT 0.0000 150.9850 26.6600 151.4150 ;
      RECT 0.0000 151.4150 28.1400 153.5050 ;
      RECT 0.0000 153.5050 26.6600 153.9350 ;
      RECT 0.0000 153.9350 28.1400 154.7650 ;
      RECT 25.8600 154.7650 28.1400 154.9800 ;
      RECT 0.0000 154.7650 22.6600 154.9800 ;
    LAYER Metal2 ;
      RECT 0.0000 0.0000 28.1400 2.3050 ;
      RECT 0.0000 2.3050 26.6600 2.7350 ;
      RECT 0.0000 2.7350 28.1400 4.8250 ;
      RECT 0.0000 4.8250 26.6600 5.2550 ;
      RECT 0.0000 5.2550 28.1400 7.3450 ;
      RECT 0.0000 7.3450 26.6600 7.7750 ;
      RECT 0.0000 7.7750 28.1400 9.8650 ;
      RECT 0.0000 9.8650 26.6600 10.2950 ;
      RECT 0.0000 10.2950 28.1400 12.3850 ;
      RECT 0.0000 12.3850 26.6600 12.8150 ;
      RECT 0.0000 12.8150 28.1400 14.9050 ;
      RECT 0.0000 14.9050 26.6600 15.3350 ;
      RECT 0.0000 15.3350 28.1400 17.4250 ;
      RECT 0.0000 17.4250 26.6600 17.8550 ;
      RECT 0.0000 17.8550 28.1400 19.9450 ;
      RECT 0.0000 19.9450 26.6600 20.3750 ;
      RECT 0.0000 20.3750 28.1400 22.4650 ;
      RECT 0.0000 22.4650 26.6600 22.8950 ;
      RECT 0.0000 22.8950 28.1400 24.9850 ;
      RECT 0.0000 24.9850 26.6600 25.4150 ;
      RECT 0.0000 25.4150 28.1400 27.5050 ;
      RECT 0.0000 27.5050 26.6600 27.9350 ;
      RECT 0.0000 27.9350 28.1400 30.0250 ;
      RECT 0.0000 30.0250 26.6600 30.4550 ;
      RECT 0.0000 30.4550 28.1400 32.5450 ;
      RECT 0.0000 32.5450 26.6600 32.9750 ;
      RECT 0.0000 32.9750 28.1400 35.0650 ;
      RECT 0.0000 35.0650 26.6600 35.4950 ;
      RECT 0.0000 35.4950 28.1400 37.5850 ;
      RECT 0.0000 37.5850 26.6600 38.0150 ;
      RECT 0.0000 38.0150 28.1400 40.1050 ;
      RECT 0.0000 40.1050 26.6600 40.5350 ;
      RECT 0.0000 40.5350 28.1400 42.6250 ;
      RECT 0.0000 42.6250 26.6600 43.0550 ;
      RECT 0.0000 43.0550 28.1400 45.1450 ;
      RECT 0.0000 45.1450 26.6600 45.5750 ;
      RECT 0.0000 45.5750 28.1400 47.6650 ;
      RECT 0.0000 47.6650 26.6600 48.0950 ;
      RECT 0.0000 48.0950 28.1400 50.1850 ;
      RECT 0.0000 50.1850 26.6600 50.6150 ;
      RECT 0.0000 50.6150 28.1400 52.7050 ;
      RECT 0.0000 52.7050 26.6600 53.1350 ;
      RECT 0.0000 53.1350 28.1400 55.2250 ;
      RECT 0.0000 55.2250 26.6600 55.6550 ;
      RECT 0.0000 55.6550 28.1400 57.7450 ;
      RECT 0.0000 57.7450 26.6600 58.1750 ;
      RECT 0.0000 58.1750 28.1400 60.2650 ;
      RECT 0.0000 60.2650 26.6600 60.6950 ;
      RECT 0.0000 60.6950 28.1400 62.7850 ;
      RECT 0.0000 62.7850 26.6600 63.2150 ;
      RECT 0.0000 63.2150 28.1400 65.3050 ;
      RECT 0.0000 65.3050 26.6600 65.7350 ;
      RECT 0.0000 65.7350 28.1400 67.8250 ;
      RECT 0.0000 67.8250 26.6600 68.2550 ;
      RECT 0.0000 68.2550 28.1400 70.3450 ;
      RECT 0.0000 70.3450 26.6600 70.7750 ;
      RECT 0.0000 70.7750 28.1400 72.8650 ;
      RECT 0.0000 72.8650 26.6600 73.2950 ;
      RECT 0.0000 73.2950 28.1400 75.3850 ;
      RECT 0.0000 75.3850 26.6600 75.8150 ;
      RECT 0.0000 75.8150 28.1400 77.9050 ;
      RECT 0.0000 77.9050 26.6600 78.3350 ;
      RECT 0.0000 78.3350 28.1400 80.4250 ;
      RECT 0.0000 80.4250 26.6600 80.8550 ;
      RECT 0.0000 80.8550 28.1400 82.9450 ;
      RECT 0.0000 82.9450 26.6600 83.3750 ;
      RECT 0.0000 83.3750 28.1400 85.4650 ;
      RECT 0.0000 85.4650 26.6600 85.8950 ;
      RECT 0.0000 85.8950 28.1400 87.9850 ;
      RECT 0.0000 87.9850 26.6600 88.4150 ;
      RECT 0.0000 88.4150 28.1400 90.5050 ;
      RECT 0.0000 90.5050 26.6600 90.9350 ;
      RECT 0.0000 90.9350 28.1400 93.0250 ;
      RECT 0.0000 93.0250 26.6600 93.4550 ;
      RECT 0.0000 93.4550 28.1400 95.5450 ;
      RECT 0.0000 95.5450 26.6600 95.9750 ;
      RECT 0.0000 95.9750 28.1400 98.0650 ;
      RECT 0.0000 98.0650 26.6600 98.4950 ;
      RECT 0.0000 98.4950 28.1400 100.5850 ;
      RECT 0.0000 100.5850 26.6600 101.0150 ;
      RECT 0.0000 101.0150 28.1400 103.1050 ;
      RECT 0.0000 103.1050 26.6600 103.5350 ;
      RECT 0.0000 103.5350 28.1400 105.6250 ;
      RECT 0.0000 105.6250 26.6600 106.0550 ;
      RECT 0.0000 106.0550 28.1400 108.1450 ;
      RECT 0.0000 108.1450 26.6600 108.5750 ;
      RECT 0.0000 108.5750 28.1400 110.6650 ;
      RECT 0.0000 110.6650 26.6600 111.0950 ;
      RECT 0.0000 111.0950 28.1400 113.1850 ;
      RECT 0.0000 113.1850 26.6600 113.6150 ;
      RECT 0.0000 113.6150 28.1400 115.7050 ;
      RECT 0.0000 115.7050 26.6600 116.1350 ;
      RECT 0.0000 116.1350 28.1400 118.2250 ;
      RECT 0.0000 118.2250 26.6600 118.6550 ;
      RECT 0.0000 118.6550 28.1400 120.7450 ;
      RECT 0.0000 120.7450 26.6600 121.1750 ;
      RECT 0.0000 121.1750 28.1400 123.2650 ;
      RECT 0.0000 123.2650 26.6600 123.6950 ;
      RECT 0.0000 123.6950 28.1400 125.7850 ;
      RECT 0.0000 125.7850 26.6600 126.2150 ;
      RECT 0.0000 126.2150 28.1400 128.3050 ;
      RECT 0.0000 128.3050 26.6600 128.7350 ;
      RECT 0.0000 128.7350 28.1400 130.8250 ;
      RECT 0.0000 130.8250 26.6600 131.2550 ;
      RECT 0.0000 131.2550 28.1400 133.3450 ;
      RECT 0.0000 133.3450 26.6600 133.7750 ;
      RECT 0.0000 133.7750 28.1400 135.8650 ;
      RECT 0.0000 135.8650 26.6600 136.2950 ;
      RECT 0.0000 136.2950 28.1400 138.3850 ;
      RECT 0.0000 138.3850 26.6600 138.8150 ;
      RECT 0.0000 138.8150 28.1400 140.9050 ;
      RECT 0.0000 140.9050 26.6600 141.3350 ;
      RECT 0.0000 141.3350 28.1400 143.4250 ;
      RECT 0.0000 143.4250 26.6600 143.8550 ;
      RECT 0.0000 143.8550 28.1400 145.9450 ;
      RECT 0.0000 145.9450 26.6600 146.3750 ;
      RECT 0.0000 146.3750 28.1400 148.4650 ;
      RECT 0.0000 148.4650 26.6600 148.8950 ;
      RECT 0.0000 148.8950 28.1400 150.9850 ;
      RECT 0.0000 150.9850 26.6600 151.4150 ;
      RECT 0.0000 151.4150 28.1400 153.5050 ;
      RECT 0.0000 153.5050 26.6600 153.9350 ;
      RECT 0.0000 153.9350 28.1400 154.7650 ;
      RECT 25.8600 154.7650 28.1400 154.9800 ;
      RECT 0.0000 154.7650 22.6600 154.9800 ;
    LAYER Metal1 ;
      RECT 0.0000 0.0000 28.1400 2.3250 ;
      RECT 0.0000 2.3250 26.6800 2.7150 ;
      RECT 0.0000 2.7150 28.1400 4.8450 ;
      RECT 0.0000 4.8450 26.6800 5.2350 ;
      RECT 0.0000 5.2350 28.1400 7.3650 ;
      RECT 0.0000 7.3650 26.6800 7.7550 ;
      RECT 0.0000 7.7550 28.1400 9.8850 ;
      RECT 0.0000 9.8850 26.6800 10.2750 ;
      RECT 0.0000 10.2750 28.1400 12.4050 ;
      RECT 0.0000 12.4050 26.6800 12.7950 ;
      RECT 0.0000 12.7950 28.1400 14.9250 ;
      RECT 0.0000 14.9250 26.6800 15.3150 ;
      RECT 0.0000 15.3150 28.1400 17.4450 ;
      RECT 0.0000 17.4450 26.6800 17.8350 ;
      RECT 0.0000 17.8350 28.1400 19.9650 ;
      RECT 0.0000 19.9650 26.6800 20.3550 ;
      RECT 0.0000 20.3550 28.1400 22.4850 ;
      RECT 0.0000 22.4850 26.6800 22.8750 ;
      RECT 0.0000 22.8750 28.1400 25.0050 ;
      RECT 0.0000 25.0050 26.6800 25.3950 ;
      RECT 0.0000 25.3950 28.1400 27.5250 ;
      RECT 0.0000 27.5250 26.6800 27.9150 ;
      RECT 0.0000 27.9150 28.1400 30.0450 ;
      RECT 0.0000 30.0450 26.6800 30.4350 ;
      RECT 0.0000 30.4350 28.1400 32.5650 ;
      RECT 0.0000 32.5650 26.6800 32.9550 ;
      RECT 0.0000 32.9550 28.1400 35.0850 ;
      RECT 0.0000 35.0850 26.6800 35.4750 ;
      RECT 0.0000 35.4750 28.1400 37.6050 ;
      RECT 0.0000 37.6050 26.6800 37.9950 ;
      RECT 0.0000 37.9950 28.1400 40.1250 ;
      RECT 0.0000 40.1250 26.6800 40.5150 ;
      RECT 0.0000 40.5150 28.1400 42.6450 ;
      RECT 0.0000 42.6450 26.6800 43.0350 ;
      RECT 0.0000 43.0350 28.1400 45.1650 ;
      RECT 0.0000 45.1650 26.6800 45.5550 ;
      RECT 0.0000 45.5550 28.1400 47.6850 ;
      RECT 0.0000 47.6850 26.6800 48.0750 ;
      RECT 0.0000 48.0750 28.1400 50.2050 ;
      RECT 0.0000 50.2050 26.6800 50.5950 ;
      RECT 0.0000 50.5950 28.1400 52.7250 ;
      RECT 0.0000 52.7250 26.6800 53.1150 ;
      RECT 0.0000 53.1150 28.1400 55.2450 ;
      RECT 0.0000 55.2450 26.6800 55.6350 ;
      RECT 0.0000 55.6350 28.1400 57.7650 ;
      RECT 0.0000 57.7650 26.6800 58.1550 ;
      RECT 0.0000 58.1550 28.1400 60.2850 ;
      RECT 0.0000 60.2850 26.6800 60.6750 ;
      RECT 0.0000 60.6750 28.1400 62.8050 ;
      RECT 0.0000 62.8050 26.6800 63.1950 ;
      RECT 0.0000 63.1950 28.1400 65.3250 ;
      RECT 0.0000 65.3250 26.6800 65.7150 ;
      RECT 0.0000 65.7150 28.1400 67.8450 ;
      RECT 0.0000 67.8450 26.6800 68.2350 ;
      RECT 0.0000 68.2350 28.1400 70.3650 ;
      RECT 0.0000 70.3650 26.6800 70.7550 ;
      RECT 0.0000 70.7550 28.1400 72.8850 ;
      RECT 0.0000 72.8850 26.6800 73.2750 ;
      RECT 0.0000 73.2750 28.1400 75.4050 ;
      RECT 0.0000 75.4050 26.6800 75.7950 ;
      RECT 0.0000 75.7950 28.1400 77.9250 ;
      RECT 0.0000 77.9250 26.6800 78.3150 ;
      RECT 0.0000 78.3150 28.1400 80.4450 ;
      RECT 0.0000 80.4450 26.6800 80.8350 ;
      RECT 0.0000 80.8350 28.1400 82.9650 ;
      RECT 0.0000 82.9650 26.6800 83.3550 ;
      RECT 0.0000 83.3550 28.1400 85.4850 ;
      RECT 0.0000 85.4850 26.6800 85.8750 ;
      RECT 0.0000 85.8750 28.1400 88.0050 ;
      RECT 0.0000 88.0050 26.6800 88.3950 ;
      RECT 0.0000 88.3950 28.1400 90.5250 ;
      RECT 0.0000 90.5250 26.6800 90.9150 ;
      RECT 0.0000 90.9150 28.1400 93.0450 ;
      RECT 0.0000 93.0450 26.6800 93.4350 ;
      RECT 0.0000 93.4350 28.1400 95.5650 ;
      RECT 0.0000 95.5650 26.6800 95.9550 ;
      RECT 0.0000 95.9550 28.1400 98.0850 ;
      RECT 0.0000 98.0850 26.6800 98.4750 ;
      RECT 0.0000 98.4750 28.1400 100.6050 ;
      RECT 0.0000 100.6050 26.6800 100.9950 ;
      RECT 0.0000 100.9950 28.1400 103.1250 ;
      RECT 0.0000 103.1250 26.6800 103.5150 ;
      RECT 0.0000 103.5150 28.1400 105.6450 ;
      RECT 0.0000 105.6450 26.6800 106.0350 ;
      RECT 0.0000 106.0350 28.1400 108.1650 ;
      RECT 0.0000 108.1650 26.6800 108.5550 ;
      RECT 0.0000 108.5550 28.1400 110.6850 ;
      RECT 0.0000 110.6850 26.6800 111.0750 ;
      RECT 0.0000 111.0750 28.1400 113.2050 ;
      RECT 0.0000 113.2050 26.6800 113.5950 ;
      RECT 0.0000 113.5950 28.1400 115.7250 ;
      RECT 0.0000 115.7250 26.6800 116.1150 ;
      RECT 0.0000 116.1150 28.1400 118.2450 ;
      RECT 0.0000 118.2450 26.6800 118.6350 ;
      RECT 0.0000 118.6350 28.1400 120.7650 ;
      RECT 0.0000 120.7650 26.6800 121.1550 ;
      RECT 0.0000 121.1550 28.1400 123.2850 ;
      RECT 0.0000 123.2850 26.6800 123.6750 ;
      RECT 0.0000 123.6750 28.1400 125.8050 ;
      RECT 0.0000 125.8050 26.6800 126.1950 ;
      RECT 0.0000 126.1950 28.1400 128.3250 ;
      RECT 0.0000 128.3250 26.6800 128.7150 ;
      RECT 0.0000 128.7150 28.1400 130.8450 ;
      RECT 0.0000 130.8450 26.6800 131.2350 ;
      RECT 0.0000 131.2350 28.1400 133.3650 ;
      RECT 0.0000 133.3650 26.6800 133.7550 ;
      RECT 0.0000 133.7550 28.1400 135.8850 ;
      RECT 0.0000 135.8850 26.6800 136.2750 ;
      RECT 0.0000 136.2750 28.1400 138.4050 ;
      RECT 0.0000 138.4050 26.6800 138.7950 ;
      RECT 0.0000 138.7950 28.1400 140.9250 ;
      RECT 0.0000 140.9250 26.6800 141.3150 ;
      RECT 0.0000 141.3150 28.1400 143.4450 ;
      RECT 0.0000 143.4450 26.6800 143.8350 ;
      RECT 0.0000 143.8350 28.1400 145.9650 ;
      RECT 0.0000 145.9650 26.6800 146.3550 ;
      RECT 0.0000 146.3550 28.1400 148.4850 ;
      RECT 0.0000 148.4850 26.6800 148.8750 ;
      RECT 0.0000 148.8750 28.1400 151.0050 ;
      RECT 0.0000 151.0050 26.6800 151.3950 ;
      RECT 0.0000 151.3950 28.1400 153.5250 ;
      RECT 0.0000 153.5250 26.6800 153.9150 ;
      RECT 0.0000 153.9150 28.1400 154.7850 ;
  END
END results_conv

END LIBRARY
